VERSION 5.7 ;
  NOWIREEXTENSIONATPIN ON ;
  DIVIDERCHAR "/" ;
  BUSBITCHARS "[]" ;
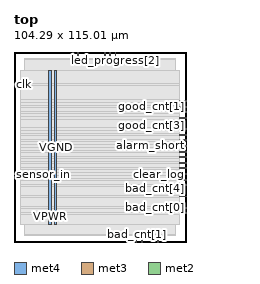
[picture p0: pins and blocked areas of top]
MACRO top
  CLASS BLOCK ;
  FOREIGN top ;
  ORIGIN 0.000 0.000 ;
  SIZE 104.290 BY 115.010 ;
  PIN VGND
    DIRECTION INOUT ;
    USE GROUND ;
    PORT
      LAYER met4 ;
        RECT 24.340 10.640 25.940 103.600 ;
    END
  END VGND
  PIN VPWR
    DIRECTION INOUT ;
    USE POWER ;
    PORT
      LAYER met4 ;
        RECT 21.040 10.640 22.640 103.600 ;
    END
  END VPWR
  PIN alarm_short
    DIRECTION OUTPUT ;
    USE SIGNAL ;
    ANTENNADIFFAREA 0.340600 ;
    PORT
      LAYER met3 ;
        RECT 100.290 57.840 104.290 58.440 ;
    END
  END alarm_short
  PIN bad_cnt[0]
    DIRECTION OUTPUT ;
    USE SIGNAL ;
    ANTENNADIFFAREA 0.340600 ;
    PORT
      LAYER met3 ;
        RECT 100.290 20.440 104.290 21.040 ;
    END
  END bad_cnt[0]
  PIN bad_cnt[1]
    DIRECTION OUTPUT ;
    USE SIGNAL ;
    ANTENNADIFFAREA 0.340600 ;
    PORT
      LAYER met2 ;
        RECT 74.150 0.000 74.430 4.000 ;
    END
  END bad_cnt[1]
  PIN bad_cnt[2]
    DIRECTION OUTPUT ;
    USE SIGNAL ;
    ANTENNADIFFAREA 0.340600 ;
    PORT
      LAYER met2 ;
        RECT 77.370 0.000 77.650 4.000 ;
    END
  END bad_cnt[2]
  PIN bad_cnt[3]
    DIRECTION OUTPUT ;
    USE SIGNAL ;
    ANTENNADIFFAREA 0.340600 ;
    PORT
      LAYER met2 ;
        RECT 87.030 0.000 87.310 4.000 ;
    END
  END bad_cnt[3]
  PIN bad_cnt[4]
    DIRECTION OUTPUT ;
    USE SIGNAL ;
    ANTENNADIFFAREA 0.340600 ;
    PORT
      LAYER met3 ;
        RECT 100.290 27.240 104.290 27.840 ;
    END
  END bad_cnt[4]
  PIN bad_cnt[5]
    DIRECTION OUTPUT ;
    USE SIGNAL ;
    ANTENNADIFFAREA 0.340600 ;
    PORT
      LAYER met3 ;
        RECT 100.290 34.040 104.290 34.640 ;
    END
  END bad_cnt[5]
  PIN bad_cnt[6]
    DIRECTION OUTPUT ;
    USE SIGNAL ;
    ANTENNADIFFAREA 0.340600 ;
    PORT
      LAYER met3 ;
        RECT 100.290 37.440 104.290 38.040 ;
    END
  END bad_cnt[6]
  PIN bad_cnt[7]
    DIRECTION OUTPUT ;
    USE SIGNAL ;
    ANTENNADIFFAREA 0.340600 ;
    PORT
      LAYER met3 ;
        RECT 100.290 44.240 104.290 44.840 ;
    END
  END bad_cnt[7]
  PIN buzzer
    DIRECTION OUTPUT ;
    USE SIGNAL ;
    ANTENNADIFFAREA 0.340600 ;
    PORT
      LAYER met3 ;
        RECT 100.290 47.640 104.290 48.240 ;
    END
  END buzzer
  PIN clear_log
    DIRECTION INPUT ;
    USE SIGNAL ;
    ANTENNAGATEAREA 0.159000 ;
    PORT
      LAYER met3 ;
        RECT 100.290 40.840 104.290 41.440 ;
    END
  END clear_log
  PIN clk
    DIRECTION INPUT ;
    USE SIGNAL ;
    ANTENNAGATEAREA 0.852000 ;
    PORT
      LAYER met3 ;
        RECT 0.000 95.240 4.000 95.840 ;
    END
  END clk
  PIN good_cnt[0]
    DIRECTION OUTPUT ;
    USE SIGNAL ;
    ANTENNADIFFAREA 0.340600 ;
    PORT
      LAYER met3 ;
        RECT 100.290 78.240 104.290 78.840 ;
    END
  END good_cnt[0]
  PIN good_cnt[1]
    DIRECTION OUTPUT ;
    USE SIGNAL ;
    ANTENNADIFFAREA 0.340600 ;
    PORT
      LAYER met3 ;
        RECT 100.290 81.640 104.290 82.240 ;
    END
  END good_cnt[1]
  PIN good_cnt[2]
    DIRECTION OUTPUT ;
    USE SIGNAL ;
    ANTENNADIFFAREA 0.340600 ;
    PORT
      LAYER met3 ;
        RECT 100.290 85.040 104.290 85.640 ;
    END
  END good_cnt[2]
  PIN good_cnt[3]
    DIRECTION OUTPUT ;
    USE SIGNAL ;
    ANTENNADIFFAREA 0.340600 ;
    PORT
      LAYER met3 ;
        RECT 100.290 74.840 104.290 75.440 ;
    END
  END good_cnt[3]
  PIN good_cnt[4]
    DIRECTION OUTPUT ;
    USE SIGNAL ;
    ANTENNADIFFAREA 0.340600 ;
    PORT
      LAYER met3 ;
        RECT 100.290 64.640 104.290 65.240 ;
    END
  END good_cnt[4]
  PIN good_cnt[5]
    DIRECTION OUTPUT ;
    USE SIGNAL ;
    ANTENNADIFFAREA 0.340600 ;
    PORT
      LAYER met3 ;
        RECT 100.290 68.040 104.290 68.640 ;
    END
  END good_cnt[5]
  PIN good_cnt[6]
    DIRECTION OUTPUT ;
    USE SIGNAL ;
    ANTENNADIFFAREA 0.340600 ;
    PORT
      LAYER met3 ;
        RECT 100.290 51.040 104.290 51.640 ;
    END
  END good_cnt[6]
  PIN good_cnt[7]
    DIRECTION OUTPUT ;
    USE SIGNAL ;
    ANTENNADIFFAREA 0.340600 ;
    PORT
      LAYER met3 ;
        RECT 100.290 54.440 104.290 55.040 ;
    END
  END good_cnt[7]
  PIN led_done
    DIRECTION OUTPUT ;
    USE SIGNAL ;
    ANTENNADIFFAREA 0.340600 ;
    PORT
      LAYER met3 ;
        RECT 100.290 61.240 104.290 61.840 ;
    END
  END led_done
  PIN led_progress[0]
    DIRECTION OUTPUT ;
    USE SIGNAL ;
    ANTENNADIFFAREA 0.340600 ;
    PORT
      LAYER met2 ;
        RECT 54.830 111.010 55.110 115.010 ;
    END
  END led_progress[0]
  PIN led_progress[1]
    DIRECTION OUTPUT ;
    USE SIGNAL ;
    ANTENNADIFFAREA 0.340600 ;
    PORT
      LAYER met2 ;
        RECT 58.050 111.010 58.330 115.010 ;
    END
  END led_progress[1]
  PIN led_progress[2]
    DIRECTION OUTPUT ;
    USE SIGNAL ;
    ANTENNADIFFAREA 0.340600 ;
    PORT
      LAYER met2 ;
        RECT 61.270 111.010 61.550 115.010 ;
    END
  END led_progress[2]
  PIN mode_sel[0]
    DIRECTION INPUT ;
    USE SIGNAL ;
    ANTENNAGATEAREA 0.196500 ;
    PORT
      LAYER met2 ;
        RECT 35.510 111.010 35.790 115.010 ;
    END
  END mode_sel[0]
  PIN mode_sel[1]
    DIRECTION INPUT ;
    USE SIGNAL ;
    ANTENNAGATEAREA 0.196500 ;
    PORT
      LAYER met2 ;
        RECT 38.730 111.010 39.010 115.010 ;
    END
  END mode_sel[1]
  PIN rst_n
    DIRECTION INPUT ;
    USE SIGNAL ;
    ANTENNAGATEAREA 0.990000 ;
    PORT
      LAYER met3 ;
        RECT 100.290 17.040 104.290 17.640 ;
    END
  END rst_n
  PIN sensor_in
    DIRECTION INPUT ;
    USE SIGNAL ;
    ANTENNAGATEAREA 0.196500 ;
    PORT
      LAYER met3 ;
        RECT 0.000 40.840 4.000 41.440 ;
    END
  END sensor_in
  OBS
      LAYER nwell ;
        RECT 5.330 10.795 98.630 103.445 ;
      LAYER li1 ;
        RECT 5.520 10.795 98.440 103.445 ;
      LAYER met1 ;
        RECT 5.520 10.640 98.440 103.600 ;
      LAYER met2 ;
        RECT 6.530 110.730 35.230 111.010 ;
        RECT 36.070 110.730 38.450 111.010 ;
        RECT 39.290 110.730 54.550 111.010 ;
        RECT 55.390 110.730 57.770 111.010 ;
        RECT 58.610 110.730 60.990 111.010 ;
        RECT 61.830 110.730 97.890 111.010 ;
        RECT 6.530 4.280 97.890 110.730 ;
        RECT 6.530 4.000 73.870 4.280 ;
        RECT 74.710 4.000 77.090 4.280 ;
        RECT 77.930 4.000 86.750 4.280 ;
        RECT 87.590 4.000 97.890 4.280 ;
      LAYER met3 ;
        RECT 4.000 96.240 100.290 103.525 ;
        RECT 4.400 94.840 100.290 96.240 ;
        RECT 4.000 86.040 100.290 94.840 ;
        RECT 4.000 84.640 99.890 86.040 ;
        RECT 4.000 82.640 100.290 84.640 ;
        RECT 4.000 81.240 99.890 82.640 ;
        RECT 4.000 79.240 100.290 81.240 ;
        RECT 4.000 77.840 99.890 79.240 ;
        RECT 4.000 75.840 100.290 77.840 ;
        RECT 4.000 74.440 99.890 75.840 ;
        RECT 4.000 69.040 100.290 74.440 ;
        RECT 4.000 67.640 99.890 69.040 ;
        RECT 4.000 65.640 100.290 67.640 ;
        RECT 4.000 64.240 99.890 65.640 ;
        RECT 4.000 62.240 100.290 64.240 ;
        RECT 4.000 60.840 99.890 62.240 ;
        RECT 4.000 58.840 100.290 60.840 ;
        RECT 4.000 57.440 99.890 58.840 ;
        RECT 4.000 55.440 100.290 57.440 ;
        RECT 4.000 54.040 99.890 55.440 ;
        RECT 4.000 52.040 100.290 54.040 ;
        RECT 4.000 50.640 99.890 52.040 ;
        RECT 4.000 48.640 100.290 50.640 ;
        RECT 4.000 47.240 99.890 48.640 ;
        RECT 4.000 45.240 100.290 47.240 ;
        RECT 4.000 43.840 99.890 45.240 ;
        RECT 4.000 41.840 100.290 43.840 ;
        RECT 4.400 40.440 99.890 41.840 ;
        RECT 4.000 38.440 100.290 40.440 ;
        RECT 4.000 37.040 99.890 38.440 ;
        RECT 4.000 35.040 100.290 37.040 ;
        RECT 4.000 33.640 99.890 35.040 ;
        RECT 4.000 28.240 100.290 33.640 ;
        RECT 4.000 26.840 99.890 28.240 ;
        RECT 4.000 21.440 100.290 26.840 ;
        RECT 4.000 20.040 99.890 21.440 ;
        RECT 4.000 18.040 100.290 20.040 ;
        RECT 4.000 16.640 99.890 18.040 ;
        RECT 4.000 10.715 100.290 16.640 ;
  END
END top
END LIBRARY

